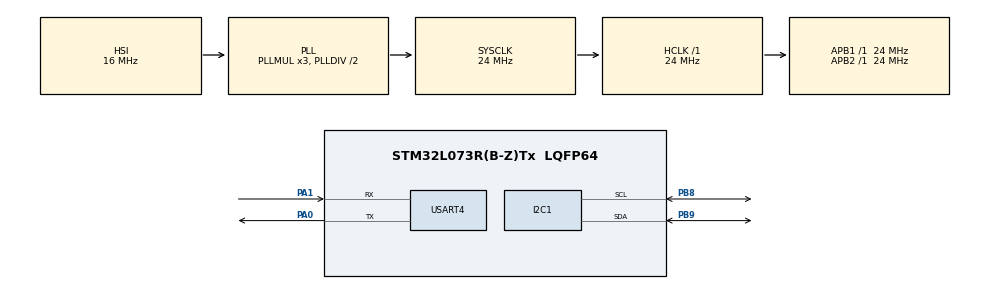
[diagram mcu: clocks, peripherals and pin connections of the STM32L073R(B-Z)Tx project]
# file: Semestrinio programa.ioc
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I2C1.Timing=0x00506682
Mcu.Family=STM32L0
Mcu.Name=STM32L073R(B-Z)Tx
Mcu.Package=LQFP64
PA0.Mode=Asynchronous
PA0.Signal=USART4_TX
PA1.Mode=Asynchronous
PA1.Signal=USART4_RX
PA13.Mode=Serial_Wire
PA13.Signal=SYS_SWDIO
PA14.Mode=Serial_Wire
PA14.Signal=SYS_SWCLK
PB8.Mode=I2C
PB8.Signal=I2C1_SCL
PB9.Mode=I2C
PB9.Signal=I2C1_SDA
PC14-OSC32_IN.Mode=LSE-External-Oscillator
PC14-OSC32_IN.Signal=RCC_OSC32_IN
PC15-OSC32_OUT.Mode=LSE-External-Oscillator
PC15-OSC32_OUT.Signal=RCC_OSC32_OUT
PH0-OSC_IN.Mode=HSE-External-Clock-Source
PH0-OSC_IN.Signal=RCC_OSC_IN
ProjectManager.HeapSize=0x200
ProjectManager.StackSize=0x400
ProjectManager.TargetToolchain=MDK-ARM V5.32
RCC.AHBFreq_Value=24000000
RCC.APB1Freq_Value=24000000
RCC.APB1TimFreq_Value=24000000
RCC.APB2Freq_Value=24000000
RCC.APB2TimFreq_Value=24000000
RCC.HCLKFreq_Value=24000000
RCC.HSE_VALUE=8000000
RCC.HSI16_VALUE=16000000
RCC.HSI48_VALUE=48000000
RCC.HSI_VALUE=16000000
RCC.MSI_VALUE=2097000
RCC.SYSCLKFreq_VALUE=24000000
RCC.SYSCLKSource=RCC_SYSCLKSOURCE_PLLCLK
RCC.VCOOutputFreq_Value=48000000
TIM6.AutoReloadPreload=TIM_AUTORELOAD_PRELOAD_ENABLE
TIM6.Period=500
TIM6.Prescaler=24000
USART4.VirtualMode-Asynchronous=VM_ASYNC
VP_TIM6_VS_ClockSourceINT.Mode=Enable_Timer
board=custom

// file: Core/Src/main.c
/* USER CODE BEGIN Header */
/**
  ******************************************************************************
  * @file           : main.c
  * @brief          : Main program body
  ******************************************************************************
  * @attention
  *
  * Copyright (c) 2024 STMicroelectronics.
  * All rights reserved.
  *
  * This software is licensed under terms that can be found in the LICENSE file
  * in the root directory of this software component.
  * If no LICENSE file comes with this software, it is provided AS-IS.
  *
  ******************************************************************************
  */
/* USER CODE END Header */
#include "main.h"

/* USER CODE BEGIN Includes */
#include "math.h"
#include "ssd1306.h"
#include "fonts.h"
#include <stdio.h>
#include "mano.h"
/* USER CODE END Includes */

/* USER CODE BEGIN PD */
#define adxl_address 0x53<<1
#define bufferlen 10
#define acc_range 2
/* USER CODE END PD */

I2C_HandleTypeDef hi2c1;

TIM_HandleTypeDef htim6;

UART_HandleTypeDef huart4;

/* USER CODE BEGIN PV */
uint8_t data_rec[6];
uint8_t chipid=0;
int16_t x,y,z;
float xg, yg, zg;
char x_char[3], y_char[3], z_char[3], g=0;
float DataBufferX[bufferlen];
float DataBufferY[bufferlen];
float DataBufferZ[bufferlen];
float RMSX, RMSY, RMSZ;

//Statechart sc_handle;

/* USER CODE END PV */

void SystemClock_Config(void);
static void MX_GPIO_Init(void);
static void MX_I2C1_Init(void);
static void MX_USART4_UART_Init(void);
static void MX_TIM6_Init(void);

/* USER CODE BEGIN 0 */
uint8_t TxBuffer[60];
int cnt=0;
int sample_no=0;
int range=0;
float divider=0;

void adxl_write (uint8_t reg, uint8_t value)
{
	uint8_t data[2];
	data[0] = reg;
	data[1] = value;
	HAL_I2C_Master_Transmit (&hi2c1, adxl_address, data, 2, 100);
}

void adxl_read_values (uint8_t reg)
{
	HAL_I2C_Mem_Read (&hi2c1, adxl_address, reg, 1, (uint8_t *)data_rec, 6, 100);
}

void adxl_read_address (uint8_t reg)
{
	HAL_I2C_Mem_Read (&hi2c1, adxl_address, reg, 1, &chipid, 1, 100);
}

void adxl_init (void)
{
	if(acc_range==2)
	{
		range=0x00;
		divider=0.003906;
	}
	else if(acc_range==4)
	{
		range=0x01;
		divider=0.0078125;
	}
	else if(acc_range==8)
	{
		range=0x10;
		divider=0.01563;
	}
	else if(acc_range==16)
	{
		range=0x11;
		divider=0.03125;
	}
	else
	{
		range=0x00;
		divider=0.003906;
	}
	adxl_read_address (0x00); // read the DEVID

	adxl_write (0x31, range);  // data_format range= +- 2g
	adxl_write (0x2d, 0x00);  // reset all bits
	adxl_write (0x2d, 0x08);  // power_cntl measure and wake up 8hz

}

void ReadI2CSensor()
{
	adxl_read_values (0x32);
	x = ((data_rec[1]<<8)|data_rec[0]);
	y = ((data_rec[3]<<8)|data_rec[2]);
	z = ((data_rec[5]<<8)|data_rec[4]);

	xg = x * divider;
	yg = y * divider;
	zg = z * divider;
}

void saveI2CSample()
{
	DataBufferX[sample_no]=xg;
	DataBufferY[sample_no]=yg;
	DataBufferZ[sample_no]=zg;
	sample_no+=1;
}

void ProcessData()
{
	int i;
	float sumX, sumY, sumZ;

	sumX=0;
	sumY=0;
	sumZ=0;

	for(int i=0;i<bufferlen;i++)
	{
		sumX+=pow(DataBufferX[i],2);
		sumY+=pow(DataBufferY[i],2);
		sumZ+=pow(DataBufferZ[i],2);
	}

	RMSX=sqrt(sumX/bufferlen);
	RMSY=sqrt(sumY/bufferlen);
	RMSZ=sqrt(sumZ/bufferlen);
}

void DisplayInfo()
{
	#ifndef DISABLE_DISPLAY
	static char string_display[30];

	// Display I2C sensor redings
	ssd1306_SetCursor(0, 0);

	// Display analog sensors readings
	ssd1306_SetCursor(0, 0); // ssd1306_SetCursor(0, 14);
	sprintf(string_display,"Xrms=%.3fg    ",RMSX);
	ssd1306_WriteString(string_display,Font_11x18, White);
	ssd1306_SetCursor(0, 22); // ssd1306_SetCursor(0, 14);
	sprintf(string_display,"Yrms=%.3fg    ",RMSY);
	ssd1306_WriteString(string_display,Font_11x18, White);
  ssd1306_SetCursor(0, 44); // ssd1306_SetCursor(0, 14);
  sprintf(string_display,"Zrms=%.3fg    ",RMSZ);
  ssd1306_WriteString(string_display,Font_11x18, White);

	// Copy all data from local screenbuffer to the screen
  ssd1306_UpdateScreen(&hi2c1);
	#endif

}

void SendToPC()
{
	sprintf((char*) TxBuffer, "\n x = %.3f g \t y = %.3f g \t z = %.3f g ", xg, yg, zg);
	HAL_UART_Transmit(&huart4, TxBuffer, sizeof(TxBuffer), 100);
}

/* USER CODE END 0 */

int main(void)
{

  /* MCU Configuration--------------------------------------------------------*/

  /* Reset of all peripherals, Initializes the Flash interface and the Systick. */
  HAL_Init();

  /* Configure the system clock */
  SystemClock_Config();

  /* Initialize all configured peripherals */
  MX_GPIO_Init();
  MX_I2C1_Init();
  MX_USART4_UART_Init();
  MX_TIM6_Init();
  /* USER CODE BEGIN 2 */
	adxl_init();  // initialize adxl
	#ifndef DISABLE_DISPLAY
  // Init lcd using one of the stm32HAL i2c typedefs
  ssd1306_Init(&hi2c1);
  // Write data to local screenbuffer
	ssd1306_SetCursor(0,0);
  ssd1306_WriteString("Starting ...",Font_11x18, White);
  ssd1306_SetCursor(0, 12);

  // Copy all data from local screenbuffer to the screen
  ssd1306_UpdateScreen(&hi2c1);
	#endif
	cnt=0;

  /* USER CODE END 2 */

  /* Infinite loop */
  while (1)
  {

    /* USER CODE BEGIN 3 */
		if (cnt==200)
		{
			ReadI2CSensor();
			saveI2CSample();
			SendToPC();
			cnt=0;

			if (sample_no==10)
			{
				ProcessData();
				DisplayInfo();
				sample_no=0;
			}
		}
  }
  /* USER CODE END 3 */
}

void SystemClock_Config(void)
{
  RCC_OscInitTypeDef RCC_OscInitStruct = {0};
  RCC_ClkInitTypeDef RCC_ClkInitStruct = {0};
  RCC_PeriphCLKInitTypeDef PeriphClkInit = {0};

  /** Configure the main internal regulator output voltage
  */
  __HAL_PWR_VOLTAGESCALING_CONFIG(PWR_REGULATOR_VOLTAGE_SCALE1);

  /** Initializes the RCC Oscillators according to the specified parameters
  * in the RCC_OscInitTypeDef structure.
  */
  RCC_OscInitStruct.OscillatorType = RCC_OSCILLATORTYPE_HSI;
  RCC_OscInitStruct.HSIState = RCC_HSI_ON;
  RCC_OscInitStruct.HSICalibrationValue = RCC_HSICALIBRATION_DEFAULT;
  RCC_OscInitStruct.PLL.PLLState = RCC_PLL_ON;
  RCC_OscInitStruct.PLL.PLLSource = RCC_PLLSOURCE_HSI;
  RCC_OscInitStruct.PLL.PLLMUL = RCC_PLLMUL_3;
  RCC_OscInitStruct.PLL.PLLDIV = RCC_PLLDIV_2;
  if (HAL_RCC_OscConfig(&RCC_OscInitStruct) != HAL_OK)
  {
    Error_Handler();
  }

  /** Initializes the CPU, AHB and APB buses clocks
  */
  RCC_ClkInitStruct.ClockType = RCC_CLOCKTYPE_HCLK|RCC_CLOCKTYPE_SYSCLK
                              |RCC_CLOCKTYPE_PCLK1|RCC_CLOCKTYPE_PCLK2;
  RCC_ClkInitStruct.SYSCLKSource = RCC_SYSCLKSOURCE_PLLCLK;
  RCC_ClkInitStruct.AHBCLKDivider = RCC_SYSCLK_DIV1;
  RCC_ClkInitStruct.APB1CLKDivider = RCC_HCLK_DIV1;
  RCC_ClkInitStruct.APB2CLKDivider = RCC_HCLK_DIV1;

  if (HAL_RCC_ClockConfig(&RCC_ClkInitStruct, FLASH_LATENCY_1) != HAL_OK)
  {
    Error_Handler();
  }
  PeriphClkInit.PeriphClockSelection = RCC_PERIPHCLK_I2C1;
  PeriphClkInit.I2c1ClockSelection = RCC_I2C1CLKSOURCE_PCLK1;
  if (HAL_RCCEx_PeriphCLKConfig(&PeriphClkInit) != HAL_OK)
  {
    Error_Handler();
  }
}

static void MX_I2C1_Init(void)
{

  hi2c1.Instance = I2C1;
  hi2c1.Init.Timing = 0x00506682;
  hi2c1.Init.OwnAddress1 = 0;
  hi2c1.Init.AddressingMode = I2C_ADDRESSINGMODE_7BIT;
  hi2c1.Init.DualAddressMode = I2C_DUALADDRESS_DISABLE;
  hi2c1.Init.OwnAddress2 = 0;
  hi2c1.Init.OwnAddress2Masks = I2C_OA2_NOMASK;
  hi2c1.Init.GeneralCallMode = I2C_GENERALCALL_DISABLE;
  hi2c1.Init.NoStretchMode = I2C_NOSTRETCH_DISABLE;
  if (HAL_I2C_Init(&hi2c1) != HAL_OK)
  {
    Error_Handler();
  }

  /** Configure Analogue filter
  */
  if (HAL_I2CEx_ConfigAnalogFilter(&hi2c1, I2C_ANALOGFILTER_ENABLE) != HAL_OK)
  {
    Error_Handler();
  }

  /** Configure Digital filter
  */
  if (HAL_I2CEx_ConfigDigitalFilter(&hi2c1, 0) != HAL_OK)
  {
    Error_Handler();
  }

}

static void MX_TIM6_Init(void)
{

  TIM_MasterConfigTypeDef sMasterConfig = {0};

  htim6.Instance = TIM6;
  htim6.Init.Prescaler = 24000;
  htim6.Init.CounterMode = TIM_COUNTERMODE_UP;
  htim6.Init.Period = 500;
  htim6.Init.AutoReloadPreload = TIM_AUTORELOAD_PRELOAD_ENABLE;
  if (HAL_TIM_Base_Init(&htim6) != HAL_OK)
  {
    Error_Handler();
  }
  sMasterConfig.MasterOutputTrigger = TIM_TRGO_RESET;
  sMasterConfig.MasterSlaveMode = TIM_MASTERSLAVEMODE_DISABLE;
  if (HAL_TIMEx_MasterConfigSynchronization(&htim6, &sMasterConfig) != HAL_OK)
  {
    Error_Handler();
  }

}

static void MX_USART4_UART_Init(void)
{

  huart4.Instance = USART4;
  huart4.Init.BaudRate = 115200;
  huart4.Init.WordLength = UART_WORDLENGTH_8B;
  huart4.Init.StopBits = UART_STOPBITS_1;
  huart4.Init.Parity = UART_PARITY_NONE;
  huart4.Init.Mode = UART_MODE_TX_RX;
  huart4.Init.HwFlowCtl = UART_HWCONTROL_NONE;
  huart4.Init.OverSampling = UART_OVERSAMPLING_16;
  huart4.Init.OneBitSampling = UART_ONE_BIT_SAMPLE_DISABLE;
  huart4.AdvancedInit.AdvFeatureInit = UART_ADVFEATURE_NO_INIT;
  if (HAL_UART_Init(&huart4) != HAL_OK)
  {
    Error_Handler();
  }

}

static void MX_GPIO_Init(void)
{
  GPIO_InitTypeDef GPIO_InitStruct = {0};

  /* GPIO Ports Clock Enable */
  __HAL_RCC_GPIOC_CLK_ENABLE();
  __HAL_RCC_GPIOH_CLK_ENABLE();
  __HAL_RCC_GPIOA_CLK_ENABLE();
  __HAL_RCC_GPIOB_CLK_ENABLE();

  /*Configure GPIO pins : PC0 PC1 */
  GPIO_InitStruct.Pin = GPIO_PIN_0|GPIO_PIN_1;
  GPIO_InitStruct.Mode = GPIO_MODE_AF_OD;
  GPIO_InitStruct.Pull = GPIO_NOPULL;
  GPIO_InitStruct.Speed = GPIO_SPEED_FREQ_VERY_HIGH;
  GPIO_InitStruct.Alternate = GPIO_AF7_I2C3;
  HAL_GPIO_Init(GPIOC, &GPIO_InitStruct);

}

void Error_Handler(void)
{
  __disable_irq();
  while (1)
  {
  }
}
